VERSION 5.8 ;
BUSBITCHARS "[]" ;
DIVIDERCHAR "/" ;
UNITS
    DATABASE MICRONS 1000 ;
END UNITS

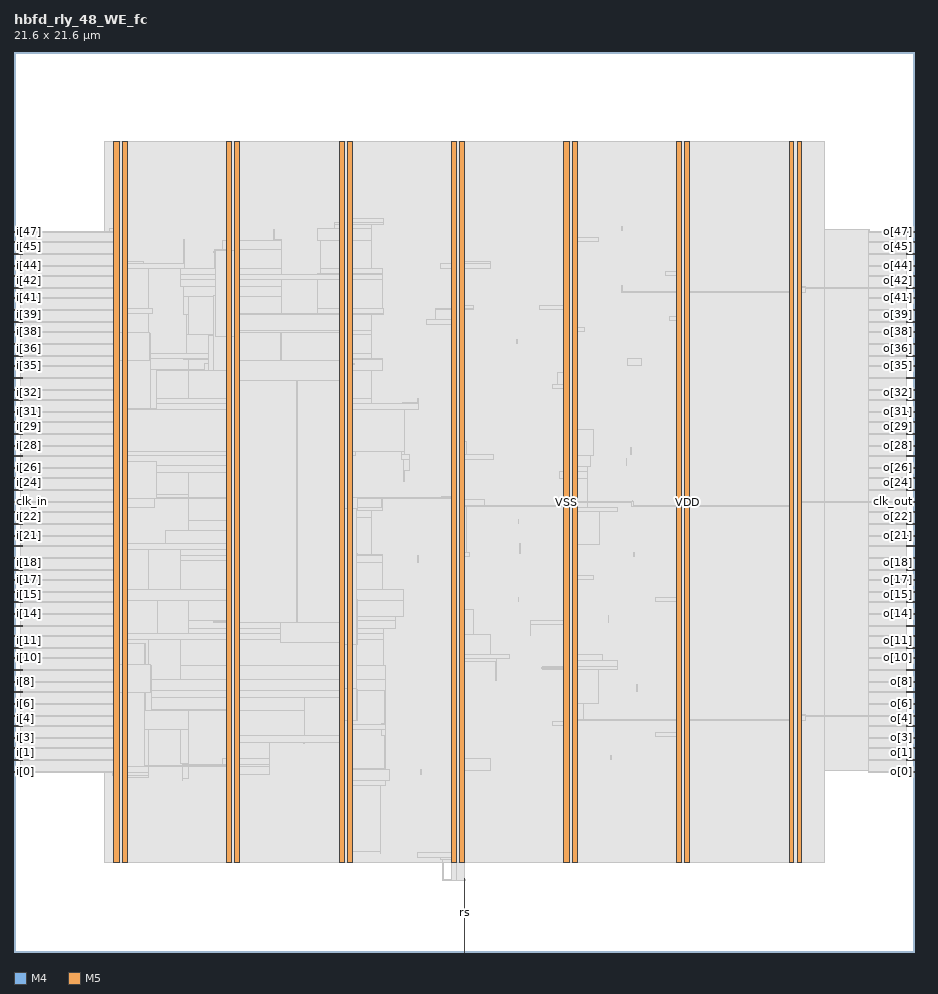
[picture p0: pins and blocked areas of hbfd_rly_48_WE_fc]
MACRO hbfd_rly_48_WE_fc
  FOREIGN hbfd_rly_48_WE_fc 0 0 ;
  CLASS BLOCK ;
  SIZE 21.6 BY 21.6 ;
  PIN clk_in
    DIRECTION INPUT ;
    USE SIGNAL ;
    PORT
      LAYER M4 ;
        RECT  0 10.8 0.192 10.824 ;
    END
  END clk_in
  PIN clk_out
    DIRECTION OUTPUT ;
    USE SIGNAL ;
    PORT
      LAYER M4 ;
        RECT  21.408 10.8 21.6 10.824 ;
    END
  END clk_out
  PIN i[0]
    DIRECTION INPUT ;
    USE SIGNAL ;
    PORT
      LAYER M4 ;
        RECT  0 4.32 0.192 4.344 ;
    END
  END i[0]
  PIN i[10]
    DIRECTION INPUT ;
    USE SIGNAL ;
    PORT
      LAYER M4 ;
        RECT  0 7.056 0.192 7.08 ;
    END
  END i[10]
  PIN i[11]
    DIRECTION INPUT ;
    USE SIGNAL ;
    PORT
      LAYER M4 ;
        RECT  0 7.296 0.192 7.32 ;
    END
  END i[11]
  PIN i[12]
    DIRECTION INPUT ;
    USE SIGNAL ;
    PORT
      LAYER M4 ;
        RECT  0 7.584 0.192 7.608 ;
    END
  END i[12]
  PIN i[13]
    DIRECTION INPUT ;
    USE SIGNAL ;
    PORT
      LAYER M4 ;
        RECT  0 7.824 0.192 7.848 ;
    END
  END i[13]
  PIN i[14]
    DIRECTION INPUT ;
    USE SIGNAL ;
    PORT
      LAYER M4 ;
        RECT  0 8.112 0.192 8.136 ;
    END
  END i[14]
  PIN i[15]
    DIRECTION INPUT ;
    USE SIGNAL ;
    PORT
      LAYER M4 ;
        RECT  0 8.4 0.192 8.424 ;
    END
  END i[15]
  PIN i[16]
    DIRECTION INPUT ;
    USE SIGNAL ;
    PORT
      LAYER M4 ;
        RECT  0 8.64 0.192 8.664 ;
    END
  END i[16]
  PIN i[17]
    DIRECTION INPUT ;
    USE SIGNAL ;
    PORT
      LAYER M4 ;
        RECT  0 8.928 0.192 8.952 ;
    END
  END i[17]
  PIN i[18]
    DIRECTION INPUT ;
    USE SIGNAL ;
    PORT
      LAYER M4 ;
        RECT  0 9.168 0.192 9.192 ;
    END
  END i[18]
  PIN i[19]
    DIRECTION INPUT ;
    USE SIGNAL ;
    PORT
      LAYER M4 ;
        RECT  0 9.456 0.192 9.48 ;
    END
  END i[19]
  PIN i[1]
    DIRECTION INPUT ;
    USE SIGNAL ;
    PORT
      LAYER M4 ;
        RECT  0 4.608 0.192 4.632 ;
    END
  END i[1]
  PIN i[20]
    DIRECTION INPUT ;
    USE SIGNAL ;
    PORT
      LAYER M4 ;
        RECT  0 9.744 0.192 9.768 ;
    END
  END i[20]
  PIN i[21]
    DIRECTION INPUT ;
    USE SIGNAL ;
    PORT
      LAYER M4 ;
        RECT  0 9.984 0.192 10.008 ;
    END
  END i[21]
  PIN i[22]
    DIRECTION INPUT ;
    USE SIGNAL ;
    PORT
      LAYER M4 ;
        RECT  0 10.272 0.192 10.296 ;
    END
  END i[22]
  PIN i[23]
    DIRECTION INPUT ;
    USE SIGNAL ;
    PORT
      LAYER M4 ;
        RECT  0 10.56 0.192 10.584 ;
    END
  END i[23]
  PIN i[24]
    DIRECTION INPUT ;
    USE SIGNAL ;
    PORT
      LAYER M4 ;
        RECT  0 11.088 0.192 11.112 ;
    END
  END i[24]
  PIN i[25]
    DIRECTION INPUT ;
    USE SIGNAL ;
    PORT
      LAYER M4 ;
        RECT  0 11.376 0.192 11.4 ;
    END
  END i[25]
  PIN i[26]
    DIRECTION INPUT ;
    USE SIGNAL ;
    PORT
      LAYER M4 ;
        RECT  0 11.616 0.192 11.64 ;
    END
  END i[26]
  PIN i[27]
    DIRECTION INPUT ;
    USE SIGNAL ;
    PORT
      LAYER M4 ;
        RECT  0 11.904 0.192 11.928 ;
    END
  END i[27]
  PIN i[28]
    DIRECTION INPUT ;
    USE SIGNAL ;
    PORT
      LAYER M4 ;
        RECT  0 12.144 0.192 12.168 ;
    END
  END i[28]
  PIN i[29]
    DIRECTION INPUT ;
    USE SIGNAL ;
    PORT
      LAYER M4 ;
        RECT  0 12.432 0.192 12.456 ;
    END
  END i[29]
  PIN i[2]
    DIRECTION INPUT ;
    USE SIGNAL ;
    PORT
      LAYER M4 ;
        RECT  0 4.896 0.192 4.92 ;
    END
  END i[2]
  PIN i[30]
    DIRECTION INPUT ;
    USE SIGNAL ;
    PORT
      LAYER M4 ;
        RECT  0 12.72 0.192 12.744 ;
    END
  END i[30]
  PIN i[31]
    DIRECTION INPUT ;
    USE SIGNAL ;
    PORT
      LAYER M4 ;
        RECT  0 12.96 0.192 12.984 ;
    END
  END i[31]
  PIN i[32]
    DIRECTION INPUT ;
    USE SIGNAL ;
    PORT
      LAYER M4 ;
        RECT  0 13.248 0.192 13.272 ;
    END
  END i[32]
  PIN i[33]
    DIRECTION INPUT ;
    USE SIGNAL ;
    PORT
      LAYER M4 ;
        RECT  0 13.488 0.192 13.512 ;
    END
  END i[33]
  PIN i[34]
    DIRECTION INPUT ;
    USE SIGNAL ;
    PORT
      LAYER M4 ;
        RECT  0 13.776 0.192 13.8 ;
    END
  END i[34]
  PIN i[35]
    DIRECTION INPUT ;
    USE SIGNAL ;
    PORT
      LAYER M4 ;
        RECT  0 14.064 0.192 14.088 ;
    END
  END i[35]
  PIN i[36]
    DIRECTION INPUT ;
    USE SIGNAL ;
    PORT
      LAYER M4 ;
        RECT  0 14.304 0.192 14.328 ;
    END
  END i[36]
  PIN i[37]
    DIRECTION INPUT ;
    USE SIGNAL ;
    PORT
      LAYER M4 ;
        RECT  0 14.592 0.192 14.616 ;
    END
  END i[37]
  PIN i[38]
    DIRECTION INPUT ;
    USE SIGNAL ;
    PORT
      LAYER M4 ;
        RECT  0 14.88 0.192 14.904 ;
    END
  END i[38]
  PIN i[39]
    DIRECTION INPUT ;
    USE SIGNAL ;
    PORT
      LAYER M4 ;
        RECT  0 15.12 0.192 15.144 ;
    END
  END i[39]
  PIN i[3]
    DIRECTION INPUT ;
    USE SIGNAL ;
    PORT
      LAYER M4 ;
        RECT  0 5.136 0.192 5.16 ;
    END
  END i[3]
  PIN i[40]
    DIRECTION INPUT ;
    USE SIGNAL ;
    PORT
      LAYER M4 ;
        RECT  0 15.408 0.192 15.432 ;
    END
  END i[40]
  PIN i[41]
    DIRECTION INPUT ;
    USE SIGNAL ;
    PORT
      LAYER M4 ;
        RECT  0 15.696 0.192 15.72 ;
    END
  END i[41]
  PIN i[42]
    DIRECTION INPUT ;
    USE SIGNAL ;
    PORT
      LAYER M4 ;
        RECT  0 15.936 0.192 15.96 ;
    END
  END i[42]
  PIN i[43]
    DIRECTION INPUT ;
    USE SIGNAL ;
    PORT
      LAYER M4 ;
        RECT  0 16.224 0.192 16.248 ;
    END
  END i[43]
  PIN i[44]
    DIRECTION INPUT ;
    USE SIGNAL ;
    PORT
      LAYER M4 ;
        RECT  0 16.464 0.192 16.488 ;
    END
  END i[44]
  PIN i[45]
    DIRECTION INPUT ;
    USE SIGNAL ;
    PORT
      LAYER M4 ;
        RECT  0 16.752 0.192 16.776 ;
    END
  END i[45]
  PIN i[46]
    DIRECTION INPUT ;
    USE SIGNAL ;
    PORT
      LAYER M4 ;
        RECT  0 17.04 0.192 17.064 ;
    END
  END i[46]
  PIN i[47]
    DIRECTION INPUT ;
    USE SIGNAL ;
    PORT
      LAYER M4 ;
        RECT  0 17.28 0.192 17.304 ;
    END
  END i[47]
  PIN i[4]
    DIRECTION INPUT ;
    USE SIGNAL ;
    PORT
      LAYER M4 ;
        RECT  0 5.424 0.192 5.448 ;
    END
  END i[4]
  PIN i[5]
    DIRECTION INPUT ;
    USE SIGNAL ;
    PORT
      LAYER M4 ;
        RECT  0 5.664 0.192 5.688 ;
    END
  END i[5]
  PIN i[6]
    DIRECTION INPUT ;
    USE SIGNAL ;
    PORT
      LAYER M4 ;
        RECT  0 5.952 0.192 5.976 ;
    END
  END i[6]
  PIN i[7]
    DIRECTION INPUT ;
    USE SIGNAL ;
    PORT
      LAYER M4 ;
        RECT  0 6.24 0.192 6.264 ;
    END
  END i[7]
  PIN i[8]
    DIRECTION INPUT ;
    USE SIGNAL ;
    PORT
      LAYER M4 ;
        RECT  0 6.48 0.192 6.504 ;
    END
  END i[8]
  PIN i[9]
    DIRECTION INPUT ;
    USE SIGNAL ;
    PORT
      LAYER M4 ;
        RECT  0 6.768 0.192 6.792 ;
    END
  END i[9]
  PIN o[0]
    DIRECTION OUTPUT ;
    USE SIGNAL ;
    PORT
      LAYER M4 ;
        RECT  21.408 4.32 21.6 4.344 ;
    END
  END o[0]
  PIN o[10]
    DIRECTION OUTPUT ;
    USE SIGNAL ;
    PORT
      LAYER M4 ;
        RECT  21.408 7.056 21.6 7.08 ;
    END
  END o[10]
  PIN o[11]
    DIRECTION OUTPUT ;
    USE SIGNAL ;
    PORT
      LAYER M4 ;
        RECT  21.408 7.296 21.6 7.32 ;
    END
  END o[11]
  PIN o[12]
    DIRECTION OUTPUT ;
    USE SIGNAL ;
    PORT
      LAYER M4 ;
        RECT  21.408 7.584 21.6 7.608 ;
    END
  END o[12]
  PIN o[13]
    DIRECTION OUTPUT ;
    USE SIGNAL ;
    PORT
      LAYER M4 ;
        RECT  21.408 7.824 21.6 7.848 ;
    END
  END o[13]
  PIN o[14]
    DIRECTION OUTPUT ;
    USE SIGNAL ;
    PORT
      LAYER M4 ;
        RECT  21.408 8.112 21.6 8.136 ;
    END
  END o[14]
  PIN o[15]
    DIRECTION OUTPUT ;
    USE SIGNAL ;
    PORT
      LAYER M4 ;
        RECT  21.408 8.4 21.6 8.424 ;
    END
  END o[15]
  PIN o[16]
    DIRECTION OUTPUT ;
    USE SIGNAL ;
    PORT
      LAYER M4 ;
        RECT  21.408 8.64 21.6 8.664 ;
    END
  END o[16]
  PIN o[17]
    DIRECTION OUTPUT ;
    USE SIGNAL ;
    PORT
      LAYER M4 ;
        RECT  21.408 8.928 21.6 8.952 ;
    END
  END o[17]
  PIN o[18]
    DIRECTION OUTPUT ;
    USE SIGNAL ;
    PORT
      LAYER M4 ;
        RECT  21.408 9.168 21.6 9.192 ;
    END
  END o[18]
  PIN o[19]
    DIRECTION OUTPUT ;
    USE SIGNAL ;
    PORT
      LAYER M4 ;
        RECT  21.408 9.456 21.6 9.48 ;
    END
  END o[19]
  PIN o[1]
    DIRECTION OUTPUT ;
    USE SIGNAL ;
    PORT
      LAYER M4 ;
        RECT  21.408 4.608 21.6 4.632 ;
    END
  END o[1]
  PIN o[20]
    DIRECTION OUTPUT ;
    USE SIGNAL ;
    PORT
      LAYER M4 ;
        RECT  21.408 9.744 21.6 9.768 ;
    END
  END o[20]
  PIN o[21]
    DIRECTION OUTPUT ;
    USE SIGNAL ;
    PORT
      LAYER M4 ;
        RECT  21.408 9.984 21.6 10.008 ;
    END
  END o[21]
  PIN o[22]
    DIRECTION OUTPUT ;
    USE SIGNAL ;
    PORT
      LAYER M4 ;
        RECT  21.408 10.272 21.6 10.296 ;
    END
  END o[22]
  PIN o[23]
    DIRECTION OUTPUT ;
    USE SIGNAL ;
    PORT
      LAYER M4 ;
        RECT  21.408 10.56 21.6 10.584 ;
    END
  END o[23]
  PIN o[24]
    DIRECTION OUTPUT ;
    USE SIGNAL ;
    PORT
      LAYER M4 ;
        RECT  21.408 11.088 21.6 11.112 ;
    END
  END o[24]
  PIN o[25]
    DIRECTION OUTPUT ;
    USE SIGNAL ;
    PORT
      LAYER M4 ;
        RECT  21.408 11.376 21.6 11.4 ;
    END
  END o[25]
  PIN o[26]
    DIRECTION OUTPUT ;
    USE SIGNAL ;
    PORT
      LAYER M4 ;
        RECT  21.408 11.616 21.6 11.64 ;
    END
  END o[26]
  PIN o[27]
    DIRECTION OUTPUT ;
    USE SIGNAL ;
    PORT
      LAYER M4 ;
        RECT  21.408 11.904 21.6 11.928 ;
    END
  END o[27]
  PIN o[28]
    DIRECTION OUTPUT ;
    USE SIGNAL ;
    PORT
      LAYER M4 ;
        RECT  21.408 12.144 21.6 12.168 ;
    END
  END o[28]
  PIN o[29]
    DIRECTION OUTPUT ;
    USE SIGNAL ;
    PORT
      LAYER M4 ;
        RECT  21.408 12.432 21.6 12.456 ;
    END
  END o[29]
  PIN o[2]
    DIRECTION OUTPUT ;
    USE SIGNAL ;
    PORT
      LAYER M4 ;
        RECT  21.408 4.896 21.6 4.92 ;
    END
  END o[2]
  PIN o[30]
    DIRECTION OUTPUT ;
    USE SIGNAL ;
    PORT
      LAYER M4 ;
        RECT  21.408 12.72 21.6 12.744 ;
    END
  END o[30]
  PIN o[31]
    DIRECTION OUTPUT ;
    USE SIGNAL ;
    PORT
      LAYER M4 ;
        RECT  21.408 12.96 21.6 12.984 ;
    END
  END o[31]
  PIN o[32]
    DIRECTION OUTPUT ;
    USE SIGNAL ;
    PORT
      LAYER M4 ;
        RECT  21.408 13.248 21.6 13.272 ;
    END
  END o[32]
  PIN o[33]
    DIRECTION OUTPUT ;
    USE SIGNAL ;
    PORT
      LAYER M4 ;
        RECT  21.408 13.488 21.6 13.512 ;
    END
  END o[33]
  PIN o[34]
    DIRECTION OUTPUT ;
    USE SIGNAL ;
    PORT
      LAYER M4 ;
        RECT  21.408 13.776 21.6 13.8 ;
    END
  END o[34]
  PIN o[35]
    DIRECTION OUTPUT ;
    USE SIGNAL ;
    PORT
      LAYER M4 ;
        RECT  21.408 14.064 21.6 14.088 ;
    END
  END o[35]
  PIN o[36]
    DIRECTION OUTPUT ;
    USE SIGNAL ;
    PORT
      LAYER M4 ;
        RECT  21.408 14.304 21.6 14.328 ;
    END
  END o[36]
  PIN o[37]
    DIRECTION OUTPUT ;
    USE SIGNAL ;
    PORT
      LAYER M4 ;
        RECT  21.408 14.592 21.6 14.616 ;
    END
  END o[37]
  PIN o[38]
    DIRECTION OUTPUT ;
    USE SIGNAL ;
    PORT
      LAYER M4 ;
        RECT  21.408 14.88 21.6 14.904 ;
    END
  END o[38]
  PIN o[39]
    DIRECTION OUTPUT ;
    USE SIGNAL ;
    PORT
      LAYER M4 ;
        RECT  21.408 15.12 21.6 15.144 ;
    END
  END o[39]
  PIN o[3]
    DIRECTION OUTPUT ;
    USE SIGNAL ;
    PORT
      LAYER M4 ;
        RECT  21.408 5.136 21.6 5.16 ;
    END
  END o[3]
  PIN o[40]
    DIRECTION OUTPUT ;
    USE SIGNAL ;
    PORT
      LAYER M4 ;
        RECT  21.408 15.408 21.6 15.432 ;
    END
  END o[40]
  PIN o[41]
    DIRECTION OUTPUT ;
    USE SIGNAL ;
    PORT
      LAYER M4 ;
        RECT  21.408 15.696 21.6 15.72 ;
    END
  END o[41]
  PIN o[42]
    DIRECTION OUTPUT ;
    USE SIGNAL ;
    PORT
      LAYER M4 ;
        RECT  21.408 15.936 21.6 15.96 ;
    END
  END o[42]
  PIN o[43]
    DIRECTION OUTPUT ;
    USE SIGNAL ;
    PORT
      LAYER M4 ;
        RECT  21.408 16.224 21.6 16.248 ;
    END
  END o[43]
  PIN o[44]
    DIRECTION OUTPUT ;
    USE SIGNAL ;
    PORT
      LAYER M4 ;
        RECT  21.408 16.464 21.6 16.488 ;
    END
  END o[44]
  PIN o[45]
    DIRECTION OUTPUT ;
    USE SIGNAL ;
    PORT
      LAYER M4 ;
        RECT  21.408 16.752 21.6 16.776 ;
    END
  END o[45]
  PIN o[46]
    DIRECTION OUTPUT ;
    USE SIGNAL ;
    PORT
      LAYER M4 ;
        RECT  21.408 17.04 21.6 17.064 ;
    END
  END o[46]
  PIN o[47]
    DIRECTION OUTPUT ;
    USE SIGNAL ;
    PORT
      LAYER M4 ;
        RECT  21.408 17.28 21.6 17.304 ;
    END
  END o[47]
  PIN o[4]
    DIRECTION OUTPUT ;
    USE SIGNAL ;
    PORT
      LAYER M4 ;
        RECT  21.408 5.424 21.6 5.448 ;
    END
  END o[4]
  PIN o[5]
    DIRECTION OUTPUT ;
    USE SIGNAL ;
    PORT
      LAYER M4 ;
        RECT  21.408 5.664 21.6 5.688 ;
    END
  END o[5]
  PIN o[6]
    DIRECTION OUTPUT ;
    USE SIGNAL ;
    PORT
      LAYER M4 ;
        RECT  21.408 5.952 21.6 5.976 ;
    END
  END o[6]
  PIN o[7]
    DIRECTION OUTPUT ;
    USE SIGNAL ;
    PORT
      LAYER M4 ;
        RECT  21.408 6.24 21.6 6.264 ;
    END
  END o[7]
  PIN o[8]
    DIRECTION OUTPUT ;
    USE SIGNAL ;
    PORT
      LAYER M4 ;
        RECT  21.408 6.48 21.6 6.504 ;
    END
  END o[8]
  PIN o[9]
    DIRECTION OUTPUT ;
    USE SIGNAL ;
    PORT
      LAYER M4 ;
        RECT  21.408 6.768 21.6 6.792 ;
    END
  END o[9]
  PIN rs
    DIRECTION INPUT ;
    USE SIGNAL ;
    PORT
      LAYER M5 ;
        RECT  10.8 0 10.824 0.192 ;
    END
    PORT
      LAYER M5 ;
        RECT  10.8 0.144 10.824 1.763 ;
    END
  END rs
  PIN VDD
    DIRECTION INOUT ;
    USE POWER ;
    PORT
      LAYER M5 ;
        RECT  18.792 2.151 18.912 19.449 ;
        RECT  16.092 2.151 16.212 19.449 ;
        RECT  13.392 2.151 13.512 19.449 ;
        RECT  10.692 2.151 10.812 19.449 ;
        RECT  7.992 2.151 8.112 19.449 ;
        RECT  5.292 2.151 5.412 19.449 ;
        RECT  2.592 2.151 2.712 19.449 ;
    END
  END VDD
  PIN VSS
    DIRECTION INOUT ;
    USE GROUND ;
    PORT
      LAYER M5 ;
        RECT  18.6 2.137 18.72 19.463 ;
        RECT  15.9 2.137 16.02 19.463 ;
        RECT  13.2 2.137 13.32 19.463 ;
        RECT  10.5 2.137 10.62 19.463 ;
        RECT  7.8 2.137 7.92 19.463 ;
        RECT  5.1 2.137 5.22 19.463 ;
        RECT  2.4 2.137 2.52 19.463 ;
    END
  END VSS
  # OT_OBS_CLOSED layer=M5 d_um=1.536 added=6
  OBS
    LAYER RVTN ;
     RECT  2.16 2.16 19.44 2.295 ;
     RECT  2.16 2.565 19.44 2.835 ;
     RECT  2.16 3.105 19.44 3.375 ;
     RECT  2.16 3.645 19.44 3.915 ;
     RECT  2.16 4.185 19.44 4.455 ;
     RECT  2.16 4.725 19.44 4.995 ;
     RECT  2.16 5.265 19.44 5.535 ;
     RECT  2.16 5.805 19.44 6.075 ;
     RECT  2.16 6.345 19.44 6.615 ;
     RECT  2.16 6.885 19.44 7.155 ;
     RECT  2.16 7.425 19.44 7.695 ;
     RECT  2.16 7.965 19.44 8.235 ;
     RECT  2.16 8.505 19.44 8.775 ;
     RECT  2.16 9.045 19.44 9.315 ;
     RECT  2.16 9.585 19.44 9.855 ;
     RECT  2.16 10.125 19.44 10.395 ;
     RECT  2.16 10.665 19.44 10.935 ;
     RECT  2.16 11.205 19.44 11.475 ;
     RECT  2.16 11.745 19.44 12.015 ;
     RECT  2.16 12.285 19.44 12.555 ;
     RECT  2.16 12.825 19.44 13.095 ;
     RECT  2.16 13.365 19.44 13.635 ;
     RECT  2.16 13.905 19.44 14.175 ;
     RECT  2.16 14.445 19.44 14.715 ;
     RECT  2.16 14.985 19.44 15.255 ;
     RECT  2.16 15.525 19.44 15.795 ;
     RECT  2.16 16.065 19.44 16.335 ;
     RECT  2.16 16.605 19.44 16.875 ;
     RECT  2.16 17.145 19.44 17.415 ;
     RECT  2.16 17.685 19.44 17.955 ;
     RECT  2.16 18.225 19.44 18.495 ;
     RECT  2.16 18.765 19.44 19.035 ;
     RECT  2.16 19.305 19.44 19.44 ;
    LAYER RVTP ;
     RECT  2.16 2.295 19.44 2.565 ;
     RECT  2.16 2.835 19.44 3.105 ;
     RECT  2.16 3.375 19.44 3.645 ;
     RECT  2.16 3.915 19.44 4.185 ;
     RECT  2.16 4.455 19.44 4.725 ;
     RECT  2.16 4.995 19.44 5.265 ;
     RECT  2.16 5.535 19.44 5.805 ;
     RECT  2.16 6.075 19.44 6.345 ;
     RECT  2.16 6.615 19.44 6.885 ;
     RECT  2.16 7.155 19.44 7.425 ;
     RECT  2.16 7.695 19.44 7.965 ;
     RECT  2.16 8.235 19.44 8.505 ;
     RECT  2.16 8.775 19.44 9.045 ;
     RECT  2.16 9.315 19.44 9.585 ;
     RECT  2.16 9.855 19.44 10.125 ;
     RECT  2.16 10.395 19.44 10.665 ;
     RECT  2.16 10.935 19.44 11.205 ;
     RECT  2.16 11.475 19.44 11.745 ;
     RECT  2.16 12.015 19.44 12.285 ;
     RECT  2.16 12.555 19.44 12.825 ;
     RECT  2.16 13.095 19.44 13.365 ;
     RECT  2.16 13.635 19.44 13.905 ;
     RECT  2.16 14.175 19.44 14.445 ;
     RECT  2.16 14.715 19.44 14.985 ;
     RECT  2.16 15.255 19.44 15.525 ;
     RECT  2.16 15.795 19.44 16.065 ;
     RECT  2.16 16.335 19.44 16.605 ;
     RECT  2.16 16.875 19.44 17.145 ;
     RECT  2.16 17.415 19.44 17.685 ;
     RECT  2.16 17.955 19.44 18.225 ;
     RECT  2.16 18.495 19.44 18.765 ;
     RECT  2.16 19.035 19.44 19.305 ;
    LAYER M1 ;
     RECT  2.16 2.151 19.44 19.449 ;
    LAYER M2 ;
     RECT  2.16 2.151 19.44 19.449 ;
     RECT  19.44 4.356 20.543 17.334 ;
    LAYER M3 ;
     RECT  10.296 1.723 10.314 2.143 ;
     RECT  10.296 2.143 10.605 2.227 ;
     RECT  10.224 2.227 10.605 2.263 ;
     RECT  9.684 2.263 10.605 2.399 ;
     RECT  2.415 2.143 2.505 2.413 ;
     RECT  5.115 2.143 5.205 2.413 ;
     RECT  7.815 2.143 7.905 2.413 ;
     RECT  8.784 2.371 8.802 2.413 ;
     RECT  10.515 2.399 10.605 2.413 ;
     RECT  13.215 2.143 13.305 2.413 ;
     RECT  15.915 2.143 16.005 2.413 ;
     RECT  18.615 2.143 18.705 2.413 ;
     RECT  7.815 2.413 8.802 3.991 ;
     RECT  7.815 3.991 8.91 4.117 ;
     RECT  4.032 4.117 4.05 4.153 ;
     RECT  2.415 2.413 2.697 4.189 ;
     RECT  2.415 4.189 3.222 4.225 ;
     RECT  5.115 2.413 5.397 4.261 ;
     RECT  2.376 4.225 3.222 4.315 ;
     RECT  10.515 2.413 10.797 4.351 ;
     RECT  7.815 4.117 9.018 4.379 ;
     RECT  9.756 4.261 9.774 4.379 ;
     RECT  13.215 2.413 13.497 4.387 ;
     RECT  7.815 4.379 8.91 4.415 ;
     RECT  4.032 4.153 4.194 4.453 ;
     RECT  5.115 4.261 6.138 4.453 ;
     RECT  4.032 4.453 6.138 4.493 ;
     RECT  4.032 4.493 4.194 4.531 ;
     RECT  13.212 4.387 13.497 4.559 ;
     RECT  5.004 4.493 6.138 4.649 ;
     RECT  10.515 4.351 11.43 4.649 ;
     RECT  14.328 4.621 14.346 4.721 ;
     RECT  13.215 4.559 13.497 4.891 ;
     RECT  5.115 4.649 6.138 5.035 ;
     RECT  6.948 4.999 6.966 5.035 ;
     RECT  7.815 4.415 8.097 5.035 ;
     RECT  15.915 2.413 16.197 5.161 ;
     RECT  5.115 5.035 8.097 5.189 ;
     RECT  8.892 4.415 8.91 5.197 ;
     RECT  0.216 5.131 0.234 5.261 ;
     RECT  15.408 5.161 16.197 5.261 ;
     RECT  2.304 4.315 3.222 5.341 ;
     RECT  3.996 4.531 4.194 5.341 ;
     RECT  7.815 5.189 8.097 5.341 ;
     RECT  8.82 5.197 8.91 5.341 ;
     RECT  13.215 4.891 13.518 5.431 ;
     RECT  7.815 5.341 8.91 5.459 ;
     RECT  8.82 5.459 8.91 5.495 ;
     RECT  12.924 5.431 13.518 5.531 ;
     RECT  13.212 5.531 13.518 5.563 ;
     RECT  18.615 2.413 18.897 5.563 ;
     RECT  18.615 5.563 18.99 5.693 ;
     RECT  2.304 5.341 4.194 5.803 ;
     RECT  5.115 5.189 6.966 5.803 ;
     RECT  13.212 5.563 13.662 5.971 ;
     RECT  2.304 5.803 6.966 6.115 ;
     RECT  7.815 5.459 8.097 6.115 ;
     RECT  8.892 5.495 8.91 6.277 ;
     RECT  2.304 6.115 8.097 6.283 ;
     RECT  8.82 6.277 8.91 6.283 ;
     RECT  14.94 6.241 14.958 6.413 ;
     RECT  2.304 6.283 8.91 6.539 ;
     RECT  13.212 5.971 14.022 6.781 ;
     RECT  12.672 6.781 14.49 6.845 ;
     RECT  3.996 6.539 8.91 6.881 ;
     RECT  10.515 4.649 10.797 6.961 ;
     RECT  11.556 6.511 11.574 6.961 ;
     RECT  13.215 6.845 14.49 6.989 ;
     RECT  10.515 6.961 11.574 7.051 ;
     RECT  10.515 7.051 11.898 7.151 ;
     RECT  13.215 6.989 14.13 7.151 ;
     RECT  0.216 7.291 0.234 7.421 ;
     RECT  2.304 6.539 3.222 7.501 ;
     RECT  3.996 6.881 8.874 7.501 ;
     RECT  10.515 7.151 11.43 7.619 ;
     RECT  2.304 7.501 8.874 7.655 ;
     RECT  4.176 7.655 8.874 7.771 ;
     RECT  12.384 7.591 12.402 7.861 ;
     RECT  13.215 7.151 13.497 7.861 ;
     RECT  4.176 7.771 9.162 7.961 ;
     RECT  12.384 7.861 13.497 7.961 ;
     RECT  7.308 7.961 9.162 8.041 ;
     RECT  14.256 7.897 14.274 8.069 ;
     RECT  10.515 7.619 11.034 8.231 ;
     RECT  15.915 5.261 16.197 8.401 ;
     RECT  7.308 8.041 9.342 8.429 ;
     RECT  2.304 7.655 3.438 8.437 ;
     RECT  4.176 7.961 6.426 8.437 ;
     RECT  12.096 8.401 12.114 8.501 ;
     RECT  15.408 8.401 16.197 8.501 ;
     RECT  2.304 8.437 6.426 8.699 ;
     RECT  7.344 8.429 9.342 8.699 ;
     RECT  13.215 7.961 13.497 8.941 ;
     RECT  13.215 8.941 13.914 9.041 ;
     RECT  7.344 8.699 8.838 9.355 ;
     RECT  3.996 8.699 6.426 9.391 ;
     RECT  10.515 8.231 10.797 9.481 ;
     RECT  3.996 9.391 6.57 9.509 ;
     RECT  7.308 9.355 8.838 9.509 ;
     RECT  9.684 9.355 9.702 9.509 ;
     RECT  7.344 9.509 8.838 9.545 ;
     RECT  10.515 9.481 10.926 9.581 ;
     RECT  14.868 9.481 14.886 9.581 ;
     RECT  2.304 8.699 3.222 9.661 ;
     RECT  3.996 9.509 6.426 9.661 ;
     RECT  13.215 9.041 13.497 9.787 ;
     RECT  2.304 9.661 6.426 9.815 ;
     RECT  12.132 9.553 12.15 9.815 ;
     RECT  3.636 9.815 6.426 10.121 ;
     RECT  4.176 10.121 6.426 10.355 ;
     RECT  12.096 10.291 12.114 10.391 ;
     RECT  7.344 9.545 8.586 10.435 ;
     RECT  5.115 10.355 6.426 10.471 ;
     RECT  13.215 9.787 14.058 10.561 ;
     RECT  7.308 10.435 8.586 10.597 ;
     RECT  7.308 10.597 8.838 10.661 ;
     RECT  13.215 10.561 14.49 10.661 ;
     RECT  2.304 9.815 2.697 10.669 ;
     RECT  5.115 10.471 6.57 10.669 ;
     RECT  7.308 10.661 8.097 10.669 ;
     RECT  10.515 9.581 10.854 10.699 ;
     RECT  5.115 10.669 8.097 10.769 ;
     RECT  14.832 10.699 14.85 10.829 ;
     RECT  10.515 10.699 11.286 10.859 ;
     RECT  10.515 10.859 10.797 10.891 ;
     RECT  6.948 10.769 8.097 10.895 ;
     RECT  8.82 10.661 8.838 10.895 ;
     RECT  10.26 10.891 10.797 10.931 ;
     RECT  2.304 10.669 3.366 10.975 ;
     RECT  4.176 10.355 4.194 10.975 ;
     RECT  13.215 10.661 13.77 11.371 ;
     RECT  2.304 10.975 4.194 11.515 ;
     RECT  5.115 10.769 6.138 11.515 ;
     RECT  13.104 11.371 13.77 11.543 ;
     RECT  9.36 11.281 9.378 11.551 ;
     RECT  13.215 11.543 13.77 11.641 ;
     RECT  2.304 11.515 6.138 11.677 ;
     RECT  6.948 10.895 6.966 11.677 ;
     RECT  7.815 10.895 8.097 11.677 ;
     RECT  9.36 11.551 9.486 11.821 ;
     RECT  10.515 10.931 10.797 11.821 ;
     RECT  14.688 11.677 14.706 11.849 ;
     RECT  2.304 11.677 8.097 11.911 ;
     RECT  13.215 11.641 13.842 11.911 ;
     RECT  0.216 11.755 0.234 11.933 ;
     RECT  9.288 11.821 9.486 11.939 ;
     RECT  10.515 11.821 11.502 11.939 ;
     RECT  2.304 11.911 8.19 12.019 ;
     RECT  9.288 11.939 9.378 12.019 ;
     RECT  14.796 11.947 14.814 12.119 ;
     RECT  10.515 11.939 10.854 12.245 ;
     RECT  13.215 11.911 13.914 12.551 ;
     RECT  2.304 12.019 9.378 13.027 ;
     RECT  0.216 12.955 0.234 13.085 ;
     RECT  2.304 13.027 9.702 13.163 ;
     RECT  9.324 13.163 9.702 13.199 ;
     RECT  2.304 13.163 8.586 13.289 ;
     RECT  9.684 13.199 9.702 13.289 ;
     RECT  2.304 13.289 3.402 13.325 ;
     RECT  13.215 12.551 13.497 13.531 ;
     RECT  12.924 13.531 13.497 13.631 ;
     RECT  13.032 13.631 13.497 13.901 ;
     RECT  4.176 13.289 8.586 13.945 ;
     RECT  4.176 13.945 8.838 14.215 ;
     RECT  4.068 14.215 8.838 14.243 ;
     RECT  14.724 14.071 15.066 14.243 ;
     RECT  2.304 13.325 3.222 14.251 ;
     RECT  4.068 14.243 8.586 14.251 ;
     RECT  2.304 14.251 8.586 14.369 ;
     RECT  12.06 14.611 12.078 14.711 ;
     RECT  4.14 14.369 8.586 14.813 ;
     RECT  13.215 13.901 13.497 14.881 ;
     RECT  5.004 14.813 8.586 14.909 ;
     RECT  13.215 14.881 13.698 14.981 ;
     RECT  10.515 12.245 10.797 15.061 ;
     RECT  15.915 8.501 16.197 15.151 ;
     RECT  9.9 15.061 10.797 15.179 ;
     RECT  15.732 15.151 16.197 15.251 ;
     RECT  4.14 14.813 4.194 15.295 ;
     RECT  5.115 14.909 8.586 15.295 ;
     RECT  5.115 15.295 8.874 15.323 ;
     RECT  2.304 14.369 3.222 15.331 ;
     RECT  10.116 15.179 10.797 15.421 ;
     RECT  13.215 14.981 13.497 15.421 ;
     RECT  2.304 15.331 3.33 15.449 ;
     RECT  7.272 15.323 8.874 15.449 ;
     RECT  10.116 15.421 11.034 15.449 ;
     RECT  10.515 15.449 11.034 15.521 ;
     RECT  12.6 15.421 13.497 15.521 ;
     RECT  4.068 15.295 4.194 15.739 ;
     RECT  5.115 15.323 6.426 15.739 ;
     RECT  18.615 5.693 18.897 15.835 ;
     RECT  4.068 15.739 6.426 15.961 ;
     RECT  18.615 15.835 18.99 15.965 ;
     RECT  14.58 15.835 14.598 15.989 ;
     RECT  3.996 15.961 6.426 16.141 ;
     RECT  7.272 15.449 8.838 16.141 ;
     RECT  15.915 15.251 16.197 16.231 ;
     RECT  3.996 16.141 8.838 16.259 ;
     RECT  7.272 16.259 8.838 16.295 ;
     RECT  15.624 16.231 16.197 16.331 ;
     RECT  3.996 16.259 6.426 16.403 ;
     RECT  7.344 16.295 8.838 16.403 ;
     RECT  2.304 15.449 3.222 16.411 ;
     RECT  3.996 16.403 4.086 16.411 ;
     RECT  10.515 15.521 10.797 16.411 ;
     RECT  2.304 16.411 4.086 16.529 ;
     RECT  10.224 16.411 11.43 16.529 ;
     RECT  2.304 16.529 3.114 16.565 ;
     RECT  10.515 16.529 11.43 16.565 ;
     RECT  4.824 16.403 6.426 16.871 ;
     RECT  13.215 15.521 13.497 17.041 ;
     RECT  5.004 16.871 6.426 17.069 ;
     RECT  7.344 16.403 8.586 17.077 ;
     RECT  4.068 16.529 4.086 17.105 ;
     RECT  6.228 17.069 6.426 17.105 ;
     RECT  13.215 17.041 14.022 17.141 ;
     RECT  6.228 17.105 6.246 17.339 ;
     RECT  20.52 4.315 20.538 17.339 ;
     RECT  2.304 16.565 2.697 17.375 ;
     RECT  7.272 17.077 8.586 17.375 ;
     RECT  14.58 17.311 14.598 17.411 ;
     RECT  7.704 17.375 8.586 17.455 ;
     RECT  7.704 17.455 8.874 17.519 ;
     RECT  7.815 17.519 8.874 17.609 ;
     RECT  2.415 17.375 2.697 19.187 ;
     RECT  5.115 17.069 5.397 19.187 ;
     RECT  7.815 17.609 8.097 19.187 ;
     RECT  10.515 16.565 10.797 19.187 ;
     RECT  13.215 17.141 13.497 19.187 ;
     RECT  15.915 16.331 16.197 19.187 ;
     RECT  18.615 15.965 18.897 19.187 ;
     RECT  2.415 19.187 2.505 19.457 ;
     RECT  5.115 19.187 5.205 19.457 ;
     RECT  7.815 19.187 7.905 19.457 ;
     RECT  10.515 19.187 10.605 19.457 ;
     RECT  13.215 19.187 13.305 19.457 ;
     RECT  15.915 19.187 16.005 19.457 ;
     RECT  18.615 19.187 18.705 19.457 ;
    LAYER M4 ;
     RECT  0.192 4.32 2.408 4.344 ;
     RECT  0.156 4.344 2.408 4.608 ;
     RECT  0.192 4.608 2.408 4.632 ;
     RECT  0.156 4.632 2.408 4.896 ;
     RECT  0.192 4.896 2.408 4.92 ;
     RECT  0.156 4.92 2.408 5.136 ;
     RECT  0.192 5.136 2.408 5.16 ;
     RECT  0.156 5.16 2.408 5.424 ;
     RECT  0.192 5.424 2.408 5.448 ;
     RECT  0.156 5.448 2.408 5.664 ;
     RECT  0.192 5.664 2.408 5.688 ;
     RECT  0.156 5.688 2.408 5.952 ;
     RECT  0.192 5.952 2.408 5.976 ;
     RECT  0.156 5.976 2.408 6.24 ;
     RECT  0.192 6.24 2.408 6.264 ;
     RECT  0.156 6.264 2.408 6.48 ;
     RECT  0.192 6.48 2.408 6.504 ;
     RECT  0.156 6.504 2.408 6.768 ;
     RECT  0.192 6.768 2.408 6.792 ;
     RECT  0.156 6.792 2.408 7.056 ;
     RECT  0.192 7.056 2.408 7.08 ;
     RECT  0.156 7.08 2.408 7.296 ;
     RECT  0.192 7.296 2.408 7.32 ;
     RECT  0.156 7.32 2.408 7.584 ;
     RECT  0.192 7.584 2.408 7.608 ;
     RECT  0.156 7.608 2.408 7.824 ;
     RECT  0.192 7.824 2.408 7.848 ;
     RECT  0.156 7.848 2.408 8.112 ;
     RECT  0.192 8.112 2.408 8.136 ;
     RECT  0.156 8.136 2.408 8.4 ;
     RECT  0.192 8.4 2.408 8.424 ;
     RECT  0.156 8.424 2.408 8.64 ;
     RECT  0.192 8.64 2.408 8.664 ;
     RECT  0.156 8.664 2.408 8.928 ;
     RECT  0.192 8.928 2.408 8.952 ;
     RECT  0.156 8.952 2.408 9.168 ;
     RECT  0.192 9.168 2.408 9.192 ;
     RECT  0.156 9.192 2.408 9.456 ;
     RECT  0.192 9.456 2.408 9.48 ;
     RECT  0.156 9.48 2.408 9.744 ;
     RECT  0.192 9.744 2.408 9.768 ;
     RECT  0.156 9.768 2.408 9.984 ;
     RECT  0.192 9.984 2.408 10.008 ;
     RECT  0.156 10.008 2.408 10.272 ;
     RECT  0.192 10.272 2.408 10.296 ;
     RECT  0.156 10.296 2.408 10.56 ;
     RECT  0.192 10.56 2.408 10.584 ;
     RECT  0.156 10.584 2.408 10.8 ;
     RECT  0.192 10.8 2.408 10.824 ;
     RECT  0.156 10.824 2.408 11.088 ;
     RECT  0.192 11.088 2.408 11.112 ;
     RECT  0.156 11.112 2.408 11.376 ;
     RECT  0.192 11.376 2.408 11.4 ;
     RECT  0.156 11.4 2.408 11.616 ;
     RECT  0.192 11.616 2.408 11.64 ;
     RECT  0.156 11.64 2.408 11.904 ;
     RECT  0.192 11.904 2.408 11.928 ;
     RECT  0.156 11.928 2.408 12.144 ;
     RECT  0.192 12.144 2.408 12.168 ;
     RECT  0.156 12.168 2.408 12.432 ;
     RECT  0.192 12.432 2.408 12.456 ;
     RECT  0.156 12.456 2.408 12.72 ;
     RECT  0.192 12.72 2.408 12.744 ;
     RECT  0.156 12.744 2.408 12.96 ;
     RECT  0.192 12.96 2.408 12.984 ;
     RECT  0.156 12.984 2.408 13.248 ;
     RECT  0.192 13.248 2.408 13.272 ;
     RECT  0.156 13.272 2.408 13.488 ;
     RECT  0.192 13.488 2.408 13.512 ;
     RECT  0.156 13.512 2.408 13.776 ;
     RECT  0.192 13.776 2.408 13.8 ;
     RECT  0.156 13.8 2.408 14.064 ;
     RECT  0.192 14.064 2.408 14.088 ;
     RECT  0.156 14.088 2.408 14.304 ;
     RECT  0.192 14.304 2.408 14.328 ;
     RECT  0.156 14.328 2.408 14.592 ;
     RECT  0.192 14.592 2.408 14.616 ;
     RECT  0.156 14.616 2.408 14.88 ;
     RECT  0.192 14.88 2.408 14.904 ;
     RECT  0.156 14.904 2.408 15.12 ;
     RECT  0.192 15.12 2.408 15.144 ;
     RECT  0.156 15.144 2.408 15.408 ;
     RECT  0.192 15.408 2.408 15.432 ;
     RECT  0.156 15.432 2.408 15.696 ;
     RECT  0.192 15.696 2.408 15.72 ;
     RECT  0.156 15.72 2.408 15.936 ;
     RECT  0.192 15.936 2.408 15.96 ;
     RECT  0.156 15.96 2.408 16.224 ;
     RECT  0.192 16.224 2.408 16.248 ;
     RECT  0.156 16.248 2.408 16.464 ;
     RECT  0.192 16.464 2.408 16.488 ;
     RECT  0.156 16.488 2.408 16.752 ;
     RECT  0.192 16.752 2.408 16.776 ;
     RECT  0.156 16.776 2.408 17.04 ;
     RECT  0.192 17.04 2.408 17.064 ;
     RECT  0.156 17.064 2.408 17.28 ;
     RECT  0.192 17.28 2.408 17.304 ;
     RECT  2.408 2.148 2.512 19.452 ;
     RECT  2.512 2.418 2.704 19.182 ;
     RECT  2.704 4.464 3.125 7.416 ;
     RECT  3.125 5.808 3.161 7.416 ;
     RECT  2.704 13.056 3.277 14.856 ;
     RECT  3.161 5.808 3.299 6.888 ;
     RECT  2.704 10.896 3.413 11.784 ;
     RECT  3.277 13.056 3.413 13.992 ;
     RECT  3.413 13.968 4.561 13.992 ;
     RECT  4.561 13.968 4.669 14.136 ;
     RECT  4.669 13.968 4.796 14.808 ;
     RECT  3.125 4.464 5.108 4.488 ;
     RECT  3.299 5.808 5.108 5.832 ;
     RECT  4.777 7.92 5.108 7.944 ;
     RECT  3.413 10.896 5.108 10.92 ;
     RECT  4.796 13.968 5.108 15.768 ;
     RECT  4.796 16.8 5.108 16.824 ;
     RECT  5.108 2.148 5.212 19.452 ;
     RECT  5.212 2.418 5.404 19.182 ;
     RECT  5.404 7.92 6.397 7.944 ;
     RECT  5.404 14.112 6.433 14.856 ;
     RECT  6.433 13.68 6.437 14.856 ;
     RECT  6.437 13.68 6.445 14.232 ;
     RECT  5.404 10.896 6.803 11.016 ;
     RECT  6.445 13.68 6.803 14.136 ;
     RECT  6.397 7.44 7.808 7.944 ;
     RECT  6.803 10.896 7.808 10.92 ;
     RECT  6.803 14.112 7.808 14.136 ;
     RECT  7.808 2.148 7.912 19.452 ;
     RECT  7.912 2.418 8.104 19.182 ;
     RECT  8.104 14.112 8.165 14.136 ;
     RECT  8.104 5.568 8.243 6.312 ;
     RECT  8.104 7.392 8.243 8.472 ;
     RECT  8.104 9.552 8.243 9.576 ;
     RECT  8.104 10.608 8.243 10.92 ;
     RECT  10.285 1.728 10.508 1.752 ;
     RECT  8.243 10.896 10.508 10.92 ;
     RECT  10.508 1.728 10.612 19.452 ;
     RECT  10.612 1.728 10.804 19.182 ;
     RECT  10.804 1.728 10.835 1.752 ;
     RECT  12.661 6.816 13.208 6.84 ;
     RECT  10.804 10.704 13.208 10.728 ;
     RECT  13.208 2.148 13.312 19.452 ;
     RECT  13.312 2.418 13.504 19.182 ;
     RECT  13.504 10.8 14.821 10.824 ;
     RECT  14.821 10.704 14.861 10.824 ;
     RECT  13.504 5.568 15.908 5.592 ;
     RECT  14.861 10.704 15.908 10.728 ;
     RECT  14.569 15.84 15.908 15.864 ;
     RECT  15.908 2.148 16.012 19.452 ;
     RECT  16.012 2.418 16.204 19.182 ;
     RECT  16.204 5.568 18.608 5.592 ;
     RECT  16.204 10.704 18.608 10.728 ;
     RECT  16.204 15.84 18.608 15.864 ;
     RECT  18.608 2.148 18.712 19.452 ;
     RECT  18.712 2.418 18.904 19.182 ;
     RECT  18.904 5.568 19.001 5.688 ;
     RECT  18.904 15.84 19.001 15.96 ;
     RECT  19.001 5.664 20.509 5.688 ;
     RECT  18.904 10.8 20.509 10.824 ;
     RECT  19.001 15.936 20.509 15.96 ;
     RECT  20.509 4.32 21.408 4.344 ;
     RECT  20.509 4.344 21.42 4.608 ;
     RECT  20.509 4.608 21.408 4.632 ;
     RECT  20.509 4.632 21.42 4.896 ;
     RECT  20.509 4.896 21.408 4.92 ;
     RECT  20.509 4.92 21.42 5.136 ;
     RECT  20.509 5.136 21.408 5.16 ;
     RECT  20.509 5.16 21.42 5.424 ;
     RECT  20.509 5.424 21.408 5.448 ;
     RECT  20.509 5.448 21.42 5.664 ;
     RECT  20.509 5.664 21.408 5.688 ;
     RECT  20.509 5.688 21.42 5.952 ;
     RECT  20.509 5.952 21.408 5.976 ;
     RECT  20.509 5.976 21.42 6.24 ;
     RECT  20.509 6.24 21.408 6.264 ;
     RECT  20.509 6.264 21.42 6.48 ;
     RECT  20.509 6.48 21.408 6.504 ;
     RECT  20.509 6.504 21.42 6.768 ;
     RECT  20.509 6.768 21.408 6.792 ;
     RECT  20.509 6.792 21.42 7.056 ;
     RECT  20.509 7.056 21.408 7.08 ;
     RECT  20.509 7.08 21.42 7.296 ;
     RECT  20.509 7.296 21.408 7.32 ;
     RECT  20.509 7.32 21.42 7.584 ;
     RECT  20.509 7.584 21.408 7.608 ;
     RECT  20.509 7.608 21.42 7.824 ;
     RECT  20.509 7.824 21.408 7.848 ;
     RECT  20.509 7.848 21.42 8.112 ;
     RECT  20.509 8.112 21.408 8.136 ;
     RECT  20.509 8.136 21.42 8.4 ;
     RECT  20.509 8.4 21.408 8.424 ;
     RECT  20.509 8.424 21.42 8.64 ;
     RECT  20.509 8.64 21.408 8.664 ;
     RECT  20.509 8.664 21.42 8.928 ;
     RECT  20.509 8.928 21.408 8.952 ;
     RECT  20.509 8.952 21.42 9.168 ;
     RECT  20.509 9.168 21.408 9.192 ;
     RECT  20.509 9.192 21.42 9.456 ;
     RECT  20.509 9.456 21.408 9.48 ;
     RECT  20.509 9.48 21.42 9.744 ;
     RECT  20.509 9.744 21.408 9.768 ;
     RECT  20.509 9.768 21.42 9.984 ;
     RECT  20.509 9.984 21.408 10.008 ;
     RECT  20.509 10.008 21.42 10.272 ;
     RECT  20.509 10.272 21.408 10.296 ;
     RECT  20.509 10.296 21.42 10.56 ;
     RECT  20.509 10.56 21.408 10.584 ;
     RECT  20.509 10.584 21.42 10.8 ;
     RECT  20.509 10.8 21.408 10.824 ;
     RECT  20.509 10.824 21.42 11.088 ;
     RECT  20.509 11.088 21.408 11.112 ;
     RECT  20.509 11.112 21.42 11.376 ;
     RECT  20.509 11.376 21.408 11.4 ;
     RECT  20.509 11.4 21.42 11.616 ;
     RECT  20.509 11.616 21.408 11.64 ;
     RECT  20.509 11.64 21.42 11.904 ;
     RECT  20.509 11.904 21.408 11.928 ;
     RECT  20.509 11.928 21.42 12.144 ;
     RECT  20.509 12.144 21.408 12.168 ;
     RECT  20.509 12.168 21.42 12.432 ;
     RECT  20.509 12.432 21.408 12.456 ;
     RECT  20.509 12.456 21.42 12.72 ;
     RECT  20.509 12.72 21.408 12.744 ;
     RECT  20.509 12.744 21.42 12.96 ;
     RECT  20.509 12.96 21.408 12.984 ;
     RECT  20.509 12.984 21.42 13.248 ;
     RECT  20.509 13.248 21.408 13.272 ;
     RECT  20.509 13.272 21.42 13.488 ;
     RECT  20.509 13.488 21.408 13.512 ;
     RECT  20.509 13.512 21.42 13.776 ;
     RECT  20.509 13.776 21.408 13.8 ;
     RECT  20.509 13.8 21.42 14.064 ;
     RECT  20.509 14.064 21.408 14.088 ;
     RECT  20.509 14.088 21.42 14.304 ;
     RECT  20.509 14.304 21.408 14.328 ;
     RECT  20.509 14.328 21.42 14.592 ;
     RECT  20.509 14.592 21.408 14.616 ;
     RECT  20.509 14.616 21.42 14.88 ;
     RECT  20.509 14.88 21.408 14.904 ;
     RECT  20.509 14.904 21.42 15.12 ;
     RECT  20.509 15.12 21.408 15.144 ;
     RECT  20.509 15.144 21.42 15.408 ;
     RECT  20.509 15.408 21.408 15.432 ;
     RECT  20.509 15.432 21.42 15.696 ;
     RECT  20.509 15.696 21.408 15.72 ;
     RECT  20.509 15.72 21.42 15.936 ;
     RECT  20.509 15.936 21.408 15.96 ;
     RECT  20.509 15.96 21.42 16.224 ;
     RECT  20.509 16.224 21.408 16.248 ;
     RECT  20.509 16.248 21.42 16.464 ;
     RECT  20.509 16.464 21.408 16.488 ;
     RECT  20.509 16.488 21.42 16.752 ;
     RECT  20.509 16.752 21.408 16.776 ;
     RECT  20.509 16.776 21.42 17.04 ;
     RECT  20.509 17.04 21.408 17.064 ;
     RECT  20.509 17.064 21.42 17.28 ;
     RECT  20.509 17.28 21.408 17.304 ;
    LAYER M5 ;
     RECT  10.8 1.763 10.812 2.137 ;
     RECT  2.4 2.137 2.52 2.151 ;
     RECT  5.1 2.137 5.22 2.151 ;
     RECT  7.8 2.137 7.92 2.151 ;
     RECT  13.2 2.137 13.32 2.151 ;
     RECT  15.9 2.137 16.02 2.151 ;
     RECT  18.6 2.137 18.72 2.151 ;
     RECT  7.8 2.151 8.112 5.557 ;
     RECT  2.4 2.151 2.712 6.229 ;
     RECT  7.8 5.557 8.232 6.323 ;
     RECT  2.4 6.229 3.288 6.899 ;
     RECT  7.8 6.323 8.112 7.381 ;
     RECT  7.8 7.381 8.232 10.643 ;
     RECT  0.192 10.789 0.216 10.931 ;
     RECT  6.768 7.909 6.792 13.715 ;
     RECT  2.4 6.899 2.712 14.197 ;
     RECT  5.1 2.151 5.412 14.773 ;
     RECT  2.4 14.197 3.24 14.867 ;
     RECT  6.384 14.197 6.408 14.867 ;
     RECT  4.848 14.773 5.412 16.835 ;
     RECT  2.4 14.867 2.712 19.449 ;
     RECT  5.1 16.835 5.412 19.449 ;
     RECT  7.8 10.643 8.112 19.449 ;
     RECT  10.5 2.137 10.812 19.449 ;
     RECT  13.2 2.151 13.512 19.449 ;
     RECT  15.9 2.151 16.212 19.449 ;
     RECT  18.6 2.151 18.912 19.449 ;
     RECT  2.4 19.449 2.52 19.463 ;
     RECT  5.1 19.449 5.22 19.463 ;
     RECT  7.8 19.449 7.92 19.463 ;
     RECT  10.5 19.449 10.62 19.463 ;
     RECT  13.2 19.449 13.32 19.463 ;
     RECT  15.9 19.449 16.02 19.463 ;
     RECT  18.6 19.449 18.72 19.463 ;
     RECT  8.112 6.323 8.232 7.381 ;
     RECT  5.412 7.909 6.768 13.715 ;
     RECT  6.792 7.909 7.8 13.715 ;
     RECT  5.412 13.715 7.8 14.197 ;
     RECT  5.412 14.197 6.384 14.867 ;
     RECT  6.408 14.197 7.8 14.867 ;
  END
END hbfd_rly_48_WE_fc
END LIBRARY
